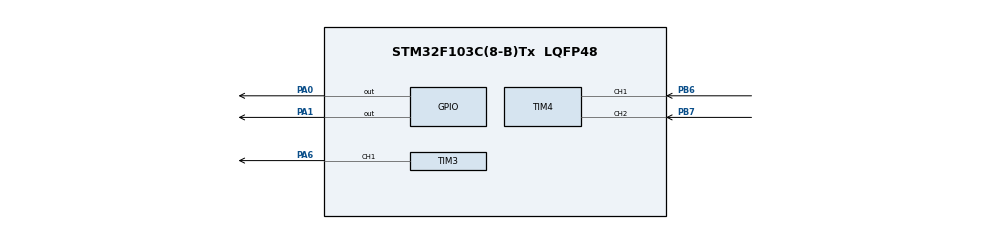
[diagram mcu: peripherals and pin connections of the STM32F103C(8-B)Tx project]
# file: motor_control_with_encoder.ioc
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Mcu.Family=STM32F1
Mcu.Name=STM32F103C(8-B)Tx
Mcu.Package=LQFP48
NVIC.PriorityGroup=NVIC_PRIORITYGROUP_4
NVIC.TIM3_IRQn=true\:0\:0\:false\:false\:true\:true\:true\:true
NVIC.TIM4_IRQn=true\:0\:0\:false\:false\:true\:true\:true\:true
PA0-WKUP.Signal=GPIO_Output
PA1.Signal=GPIO_Output
PA13.Mode=Serial_Wire
PA13.Signal=SYS_JTMS-SWDIO
PA14.Mode=Serial_Wire
PA14.Signal=SYS_JTCK-SWCLK
PA6.Signal=S_TIM3_CH1
PB6.Signal=S_TIM4_CH1
PB7.Signal=S_TIM4_CH2
PD0-OSC_IN.Mode=HSE-External-Oscillator
PD0-OSC_IN.Signal=RCC_OSC_IN
PD1-OSC_OUT.Mode=HSE-External-Oscillator
PD1-OSC_OUT.Signal=RCC_OSC_OUT
ProjectManager.HeapSize=0x200
ProjectManager.StackSize=0x400
ProjectManager.TargetToolchain=MDK-ARM V5.32
RCC.AHBFreq_Value=72000000
RCC.APB1CLKDivider=RCC_HCLK_DIV8
RCC.APB1Freq_Value=9000000
RCC.APB1TimFreq_Value=18000000
RCC.APB2Freq_Value=72000000
RCC.APB2TimFreq_Value=72000000
RCC.HCLKFreq_Value=72000000
RCC.PLLMUL=RCC_PLL_MUL9
RCC.PLLSourceVirtual=RCC_PLLSOURCE_HSE
RCC.SYSCLKFreq_VALUE=72000000
RCC.SYSCLKSource=RCC_SYSCLKSOURCE_PLLCLK
RCC.USBFreq_Value=72000000
SH.S_TIM3_CH1.0=TIM3_CH1,PWM Generation1 CH1
SH.S_TIM4_CH1.0=TIM4_CH1,Encoder_Interface
SH.S_TIM4_CH2.0=TIM4_CH2,Encoder_Interface
TIM3.AutoReloadPreload=TIM_AUTORELOAD_PRELOAD_ENABLE
TIM3.Channel-PWM\ Generation1\ CH1=TIM_CHANNEL_1
VP_TIM3_VS_ClockSourceINT.Mode=Internal
board=custom

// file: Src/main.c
#include "main.h"
#include "math.h"

#define IN1 GPIO_PIN_0
#define IN2 GPIO_PIN_1

#define KP  50.0
#define KI  200.0
#define KD  10.0

/*
#define KP  1.0
#define KI  0.4
#define KD  0.0
*/
#define MOVING_AVERAGE_LENGTH 100

TIM_HandleTypeDef htim3;
TIM_HandleTypeDef htim4;

void SystemClock_Config(void);
static void MX_GPIO_Init(void);
static void MX_TIM3_Init(void);
static void MX_TIM4_Init(void);

/* My Global Variable*/
uint16_t timer_counter = 0;
int64_t encoder_position = 0 ;
int16_t encoder_velocity = 0 ;

float rpm = 0 ;
uint16_t currentMillis = 0 ;
uint16_t PreviousMillis = 0 ;
float time_differenceMillis= 0 ;
float time_differenceSecond = 0;

int pwr=0;
float error = 0;
float errorP = 0 ;
float eintegral = 0 ;
int set_speed = 50;

float u =0;
int16_t filter_val = 0 ;
//float filter_val = 0 ;
float rpm_previous = 0;

typedef struct{
	int16_t velocity;
	int64_t position;
	uint32_t last_counter_value;

}encoder_instance ;

typedef struct{
	int16_t buffer[MOVING_AVERAGE_LENGTH];
	uint16_t counter;
	int16_t out;
	int32_t sum;
}mov_aver_instance_int16;

void update_encoder(encoder_instance *encoder_value, TIM_HandleTypeDef *htim) ;
int absolute(int num) ;
void setMotor(int dir, int pwmVal, int in1, int in2) ;
void apply_average_filter(mov_aver_instance_int16 *instance,int16_t input,int16_t *out) ;
int main(void)
{
  HAL_Init();

  SystemClock_Config();

  MX_GPIO_Init();
  MX_TIM3_Init();   //PWM
  MX_TIM4_Init();   //Encoder

	HAL_TIM_Encoder_Start_IT(&htim4,TIM_CHANNEL_ALL);

	encoder_instance enc_instance_mot;

	mov_aver_instance_int16 filter_instance1 ;

  while (1)
  {
		HAL_Delay(1) ;
		currentMillis = HAL_GetTick();
		time_differenceMillis = currentMillis-PreviousMillis ;
		time_differenceSecond = (time_differenceMillis/1000.0) ;  // sampling time

   timer_counter = __HAL_TIM_GET_COUNTER(&htim4);
  // measure velocity, position
  update_encoder(&enc_instance_mot, &htim4);
  encoder_position = enc_instance_mot.position ;
  encoder_velocity = enc_instance_mot.velocity  ;

	rpm = (float)((encoder_velocity/time_differenceSecond) * (1/44.0) * (60) * (1/35.5)) ;

	apply_average_filter(&filter_instance1,rpm,&filter_val);

//	filter_val = 0.854*filter_val + 0.0728*rpm + 0.0728*rpm_previous ; //Low Pass Filter

	error = set_speed - filter_val ;

	eintegral = 	eintegral +  error*(time_differenceSecond) ;

   u  = KP * error + KI*eintegral + (KD * (error-errorP)/time_differenceSecond) ;

//		 u  = KP * error + KI*eintegral ;
//		u  = kp * error ;
		int dir = 1 ;

		if(u<0)
		{
			dir = -1 ;

		}

		 pwr = absolute(u) ;
		if(pwr>1023)
		{
			pwr = 1023;
		}
		setMotor(dir,pwr,IN1,IN2) ;

	PreviousMillis = currentMillis ;
   rpm_previous = rpm ;
	 errorP = error ;
	 }
}

void apply_average_filter(mov_aver_instance_int16 *instance,int16_t input,int16_t *out)
{
	instance->sum +=input - instance->buffer[instance->counter];
	instance->buffer[instance->counter] = input ;
	instance->counter++;
	if(instance->counter==MOVING_AVERAGE_LENGTH)
	{
		instance->counter = 0 ;
	}
	instance->out = instance->sum /MOVING_AVERAGE_LENGTH ;

	*out = instance->out ;
}

int absolute(int num) {
    if (num < 0)
        return -num;
    else
        return num;
}

void setMotor(int dir, int pwmVal, int in1, int in2)
{
    HAL_TIM_PWM_Start(&htim3, TIM_CHANNEL_1);
	  TIM3->CCR1 = pwmVal ;
    if (dir == 1)
    {
        HAL_GPIO_WritePin(GPIOA, IN1, GPIO_PIN_RESET);   //ON
        HAL_GPIO_WritePin(GPIOA, IN2, GPIO_PIN_SET);     //OFF
    }
    else if (dir == -1)
    {
        HAL_GPIO_WritePin(GPIOA, IN1, GPIO_PIN_SET);     //OFF
        HAL_GPIO_WritePin(GPIOA, IN2, GPIO_PIN_RESET);   //ON
    }
    else
    {
        HAL_GPIO_WritePin(GPIOA, IN1, GPIO_PIN_RESET);
        HAL_GPIO_WritePin(GPIOA, IN2, GPIO_PIN_RESET);
    }
}

void update_encoder(encoder_instance *encoder_value, TIM_HandleTypeDef *htim)
 {
uint32_t temp_counter = __HAL_TIM_GET_COUNTER(htim);
static uint8_t first_time = 0;
if(!first_time)
{
   encoder_value ->velocity = 0;
   first_time = 1;
}
else
{
  if(temp_counter == encoder_value ->last_counter_value)
  {
    encoder_value ->velocity = 0;
  }
  else if(temp_counter > encoder_value ->last_counter_value)
  {
    if (__HAL_TIM_IS_TIM_COUNTING_DOWN(htim))
    {
      encoder_value ->velocity = -encoder_value ->last_counter_value -
	(__HAL_TIM_GET_AUTORELOAD(htim)-temp_counter);
    }
    else
    {
      encoder_value ->velocity = temp_counter -
           encoder_value ->last_counter_value;
    }
  }
  else
  {
    if (__HAL_TIM_IS_TIM_COUNTING_DOWN(htim))
    {
	encoder_value ->velocity = temp_counter -
            encoder_value ->last_counter_value;
    }
    else
    {
	encoder_value ->velocity = temp_counter +
	(__HAL_TIM_GET_AUTORELOAD(htim) -
              encoder_value ->last_counter_value);
    }
   }
}
encoder_value ->position += encoder_value ->velocity;
encoder_value ->last_counter_value = temp_counter;
 }

void SystemClock_Config(void)
{
  RCC_OscInitTypeDef RCC_OscInitStruct = {0};
  RCC_ClkInitTypeDef RCC_ClkInitStruct = {0};

  /** Initializes the RCC Oscillators according to the specified parameters
  * in the RCC_OscInitTypeDef structure.
  */
  RCC_OscInitStruct.OscillatorType = RCC_OSCILLATORTYPE_HSE;
  RCC_OscInitStruct.HSEState = RCC_HSE_ON;
  RCC_OscInitStruct.HSEPredivValue = RCC_HSE_PREDIV_DIV1;
  RCC_OscInitStruct.HSIState = RCC_HSI_ON;
  RCC_OscInitStruct.PLL.PLLState = RCC_PLL_ON;
  RCC_OscInitStruct.PLL.PLLSource = RCC_PLLSOURCE_HSE;
  RCC_OscInitStruct.PLL.PLLMUL = RCC_PLL_MUL9;
  if (HAL_RCC_OscConfig(&RCC_OscInitStruct) != HAL_OK)
  {
    Error_Handler();
  }

  /** Initializes the CPU, AHB and APB buses clocks
  */
  RCC_ClkInitStruct.ClockType = RCC_CLOCKTYPE_HCLK|RCC_CLOCKTYPE_SYSCLK
                              |RCC_CLOCKTYPE_PCLK1|RCC_CLOCKTYPE_PCLK2;
  RCC_ClkInitStruct.SYSCLKSource = RCC_SYSCLKSOURCE_PLLCLK;
  RCC_ClkInitStruct.AHBCLKDivider = RCC_SYSCLK_DIV1;
  RCC_ClkInitStruct.APB1CLKDivider = RCC_HCLK_DIV2;
  RCC_ClkInitStruct.APB2CLKDivider = RCC_HCLK_DIV1;

  if (HAL_RCC_ClockConfig(&RCC_ClkInitStruct, FLASH_LATENCY_2) != HAL_OK)
  {
    Error_Handler();
  }
}

static void MX_TIM3_Init(void)
{

  TIM_MasterConfigTypeDef sMasterConfig = {0};
  TIM_OC_InitTypeDef sConfigOC = {0};

  htim3.Instance = TIM3;
  htim3.Init.Prescaler = 70-1;
  htim3.Init.CounterMode = TIM_COUNTERMODE_UP;
  htim3.Init.Period = 1023-1;
  htim3.Init.ClockDivision = TIM_CLOCKDIVISION_DIV1;
  htim3.Init.AutoReloadPreload = TIM_AUTORELOAD_PRELOAD_DISABLE;
  if (HAL_TIM_PWM_Init(&htim3) != HAL_OK)
  {
    Error_Handler();
  }
  sMasterConfig.MasterOutputTrigger = TIM_TRGO_RESET;
  sMasterConfig.MasterSlaveMode = TIM_MASTERSLAVEMODE_DISABLE;
  if (HAL_TIMEx_MasterConfigSynchronization(&htim3, &sMasterConfig) != HAL_OK)
  {
    Error_Handler();
  }
  sConfigOC.OCMode = TIM_OCMODE_PWM1;
  sConfigOC.Pulse = 0;
  sConfigOC.OCPolarity = TIM_OCPOLARITY_HIGH;
  sConfigOC.OCFastMode = TIM_OCFAST_DISABLE;
  if (HAL_TIM_PWM_ConfigChannel(&htim3, &sConfigOC, TIM_CHANNEL_1) != HAL_OK)
  {
    Error_Handler();
  }
  HAL_TIM_MspPostInit(&htim3);

}

static void MX_TIM4_Init(void)
{

  TIM_Encoder_InitTypeDef sConfig = {0};
  TIM_MasterConfigTypeDef sMasterConfig = {0};

  htim4.Instance = TIM4;
  htim4.Init.Prescaler = 0;
  htim4.Init.CounterMode = TIM_COUNTERMODE_UP;
  htim4.Init.Period = 65535;
  htim4.Init.ClockDivision = TIM_CLOCKDIVISION_DIV1;
  htim4.Init.AutoReloadPreload = TIM_AUTORELOAD_PRELOAD_ENABLE;
  sConfig.EncoderMode = TIM_ENCODERMODE_TI12;
  sConfig.IC1Polarity = TIM_ICPOLARITY_RISING;
  sConfig.IC1Selection = TIM_ICSELECTION_DIRECTTI;
  sConfig.IC1Prescaler = TIM_ICPSC_DIV1;
  sConfig.IC1Filter = 10;
  sConfig.IC2Polarity = TIM_ICPOLARITY_RISING;
  sConfig.IC2Selection = TIM_ICSELECTION_DIRECTTI;
  sConfig.IC2Prescaler = TIM_ICPSC_DIV1;
  sConfig.IC2Filter = 10;
  if (HAL_TIM_Encoder_Init(&htim4, &sConfig) != HAL_OK)
  {
    Error_Handler();
  }
  sMasterConfig.MasterOutputTrigger = TIM_TRGO_RESET;
  sMasterConfig.MasterSlaveMode = TIM_MASTERSLAVEMODE_DISABLE;
  if (HAL_TIMEx_MasterConfigSynchronization(&htim4, &sMasterConfig) != HAL_OK)
  {
    Error_Handler();
  }

}

static void MX_GPIO_Init(void)
{
  GPIO_InitTypeDef GPIO_InitStruct = {0};

  /* GPIO Ports Clock Enable */
  __HAL_RCC_GPIOC_CLK_ENABLE();
  __HAL_RCC_GPIOD_CLK_ENABLE();
  __HAL_RCC_GPIOA_CLK_ENABLE();
  __HAL_RCC_GPIOB_CLK_ENABLE();

  /*Configure GPIO pin Output Level */
  HAL_GPIO_WritePin(GPIOC, GPIO_PIN_13, GPIO_PIN_RESET);

  /*Configure GPIO pin Output Level */
  HAL_GPIO_WritePin(GPIOA, GPIO_PIN_0|GPIO_PIN_1, GPIO_PIN_RESET);

  /*Configure GPIO pin : PC13 */
  GPIO_InitStruct.Pin = GPIO_PIN_13;
  GPIO_InitStruct.Mode = GPIO_MODE_OUTPUT_PP;
  GPIO_InitStruct.Pull = GPIO_NOPULL;
  GPIO_InitStruct.Speed = GPIO_SPEED_FREQ_LOW;
  HAL_GPIO_Init(GPIOC, &GPIO_InitStruct);

  /*Configure GPIO pins : PA0 PA1 */
  GPIO_InitStruct.Pin = GPIO_PIN_0|GPIO_PIN_1;
  GPIO_InitStruct.Mode = GPIO_MODE_OUTPUT_PP;
  GPIO_InitStruct.Pull = GPIO_NOPULL;
  GPIO_InitStruct.Speed = GPIO_SPEED_FREQ_LOW;
  HAL_GPIO_Init(GPIOA, &GPIO_InitStruct);

}

void Error_Handler(void)
{
  __disable_irq();
  while (1)
  {
  }
}
